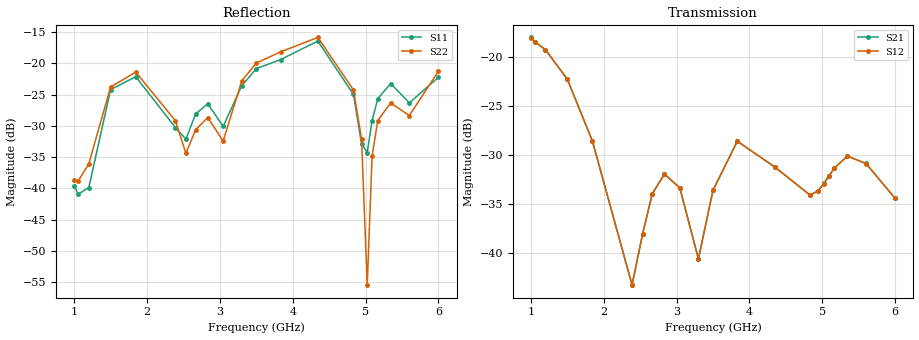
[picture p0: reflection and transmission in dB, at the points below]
!Agilent Technologies,E8364B,MY43040528,A.07.50.67
!Agilent E8364B: A.07.50.67
!Date: Sunday, March 01, 2026 20:33:12
!Correction: S11(Full 2 Port(1,2))
!S21(Full 2 Port(1,2))
!S12(Full 2 Port(1,2))
!S22(Full 2 Port(1,2))
!S2P File: Measurements: S11, S21, S12, S22:
# Hz S  dB  R 50
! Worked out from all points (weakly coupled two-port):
!   451 points, 1 GHz to 6 GHz, reference 50 ohm
!   highest |S21| = -17.95 dB at 1 GHz (marker M1); lowest = -43.3 dB at 2.389 GHz (marker M2)
!   lowest |S11| = -40.9 dB at 1.056 GHz (marker M3), VSWR 1.02, Z = 49.8 + j0.875 ohm
!   |S11| at or under -10 dB: start of sweep to end of sweep
!   |S22| runs from -55.4 to -15.6 dB; largest |S21 - S12| = 0.00035
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1e9  -39.58 77.4  -17.95 25.5  -17.98 25.5  -38.72 38.4
1.055556e9  -40.90 103.1  -18.39 9.0  -18.41 8.9  -38.77 56.4
1.2e9  -39.87 151.8  -19.20 -35.1  -19.22 -35.2  -36.08 80.0
1.5e9  -24.21 153.2  -22.23 -136.1  -22.24 -136.2  -23.78 72.9
1.844444e9  -22.15 92.4  -28.56 116.0  -28.57 116.0  -21.42 -2.2
2.388889e9  -30.27 45.2  -43.30 -119.8  -43.33 -119.8  -29.17 -87.5
2.533333e9  -32.12 77.4  -38.09 125.4  -38.12 125.4  -34.40 -67.9
2.666667e9  -28.10 84.0  -33.96 59.4  -33.98 59.3  -30.62 -49.5
2.833333e9  -26.47 63.4  -31.94 -11.8  -31.96 -11.8  -28.67 -74.6
3.044444e9  -30.09 60.6  -33.37 -93.9  -33.38 -93.9  -32.43 -69.0
3.3e9  -23.60 80.9  -40.63 -133.6  -40.66 -133.7  -22.83 -71.0
3.5e9  -20.86 54.4  -33.60 -154.6  -33.62 -154.6  -19.96 -110.0
3.833333e9  -19.42 29.4  -28.58 83.2  -28.60 83.2  -18.18 -155.4
4.344444e9  -16.46 -38.7  -31.20 -101.7  -31.22 -101.7  -15.87 111.0
4.833333e9  -24.99 -115.8  -34.10 42.1  -34.13 42.2  -24.26 0.8
4.944444e9  -32.87 -108.7  -33.65 -21.1  -33.67 -21.1  -32.11 -26.7
5.022222e9  -34.26 -49.5  -32.91 -64.5  -32.93 -64.5  -55.43 44.5
5.088889e9  -29.20 -35.5  -32.16 -100.0  -32.19 -100.0  -34.89 106.4
5.166667e9  -25.66 -41.0  -31.32 -139.3  -31.35 -139.3  -29.16 88.7
5.344444e9  -23.24 -68.7  -30.10 137.9  -30.12 137.9  -26.34 49.3
5.6e9  -26.33 -84.4  -30.86 31.4  -30.89 31.4  -28.35 41.2
6e9  -22.23 -82.7  -34.42 -83.8  -34.45 -83.8  -21.27 0.0
